VERSION 5.7 ;
BUSBITCHARS "[]" ;
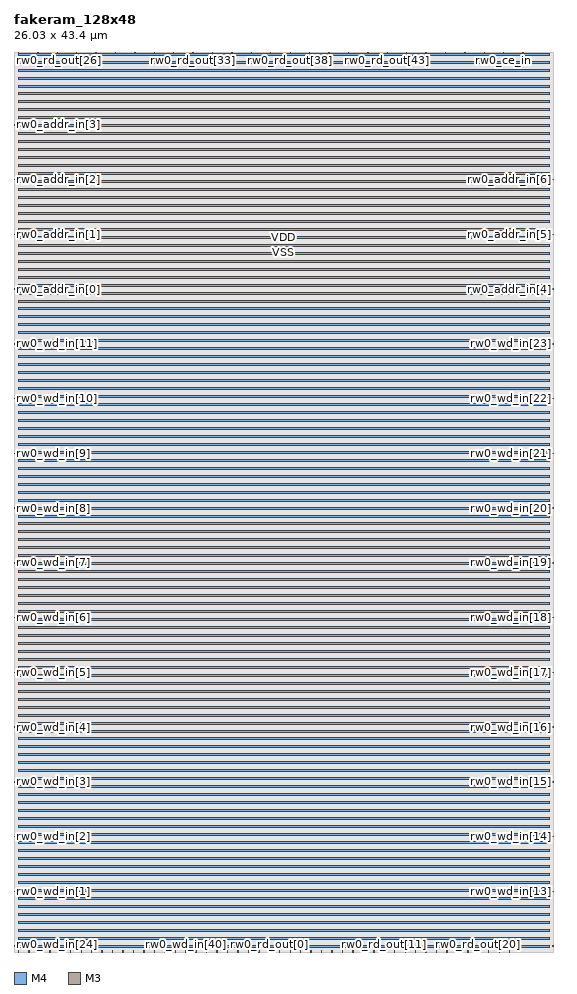
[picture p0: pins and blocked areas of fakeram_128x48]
MACRO fakeram_128x48
  FOREIGN fakeram_128x48 0 0 ;
  SYMMETRY X Y R90 ;
  SIZE 26.030 BY 43.400 ;
  CLASS BLOCK ;
  PIN rw0_wd_in[0]
    DIRECTION INPUT ;
    USE SIGNAL ;
    SHAPE ABUTMENT ;
    PORT
      LAYER M4 ;
      RECT 0.000 0.276 0.072 0.300 ;
    END
  END rw0_wd_in[0]
  PIN rw0_wd_in[1]
    DIRECTION INPUT ;
    USE SIGNAL ;
    SHAPE ABUTMENT ;
    PORT
      LAYER M4 ;
      RECT 0.000 2.916 0.072 2.940 ;
    END
  END rw0_wd_in[1]
  PIN rw0_wd_in[2]
    DIRECTION INPUT ;
    USE SIGNAL ;
    SHAPE ABUTMENT ;
    PORT
      LAYER M4 ;
      RECT 0.000 5.556 0.072 5.580 ;
    END
  END rw0_wd_in[2]
  PIN rw0_wd_in[3]
    DIRECTION INPUT ;
    USE SIGNAL ;
    SHAPE ABUTMENT ;
    PORT
      LAYER M4 ;
      RECT 0.000 8.196 0.072 8.220 ;
    END
  END rw0_wd_in[3]
  PIN rw0_wd_in[4]
    DIRECTION INPUT ;
    USE SIGNAL ;
    SHAPE ABUTMENT ;
    PORT
      LAYER M4 ;
      RECT 0.000 10.836 0.072 10.860 ;
    END
  END rw0_wd_in[4]
  PIN rw0_wd_in[5]
    DIRECTION INPUT ;
    USE SIGNAL ;
    SHAPE ABUTMENT ;
    PORT
      LAYER M4 ;
      RECT 0.000 13.476 0.072 13.500 ;
    END
  END rw0_wd_in[5]
  PIN rw0_wd_in[6]
    DIRECTION INPUT ;
    USE SIGNAL ;
    SHAPE ABUTMENT ;
    PORT
      LAYER M4 ;
      RECT 0.000 16.116 0.072 16.140 ;
    END
  END rw0_wd_in[6]
  PIN rw0_wd_in[7]
    DIRECTION INPUT ;
    USE SIGNAL ;
    SHAPE ABUTMENT ;
    PORT
      LAYER M4 ;
      RECT 0.000 18.756 0.072 18.780 ;
    END
  END rw0_wd_in[7]
  PIN rw0_wd_in[8]
    DIRECTION INPUT ;
    USE SIGNAL ;
    SHAPE ABUTMENT ;
    PORT
      LAYER M4 ;
      RECT 0.000 21.396 0.072 21.420 ;
    END
  END rw0_wd_in[8]
  PIN rw0_wd_in[9]
    DIRECTION INPUT ;
    USE SIGNAL ;
    SHAPE ABUTMENT ;
    PORT
      LAYER M4 ;
      RECT 0.000 24.036 0.072 24.060 ;
    END
  END rw0_wd_in[9]
  PIN rw0_wd_in[10]
    DIRECTION INPUT ;
    USE SIGNAL ;
    SHAPE ABUTMENT ;
    PORT
      LAYER M4 ;
      RECT 0.000 26.676 0.072 26.700 ;
    END
  END rw0_wd_in[10]
  PIN rw0_wd_in[11]
    DIRECTION INPUT ;
    USE SIGNAL ;
    SHAPE ABUTMENT ;
    PORT
      LAYER M4 ;
      RECT 0.000 29.316 0.072 29.340 ;
    END
  END rw0_wd_in[11]
  PIN rw0_wd_in[12]
    DIRECTION INPUT ;
    USE SIGNAL ;
    SHAPE ABUTMENT ;
    PORT
      LAYER M4 ;
      RECT 25.958 0.276 26.030 0.300 ;
    END
  END rw0_wd_in[12]
  PIN rw0_wd_in[13]
    DIRECTION INPUT ;
    USE SIGNAL ;
    SHAPE ABUTMENT ;
    PORT
      LAYER M4 ;
      RECT 25.958 2.916 26.030 2.940 ;
    END
  END rw0_wd_in[13]
  PIN rw0_wd_in[14]
    DIRECTION INPUT ;
    USE SIGNAL ;
    SHAPE ABUTMENT ;
    PORT
      LAYER M4 ;
      RECT 25.958 5.556 26.030 5.580 ;
    END
  END rw0_wd_in[14]
  PIN rw0_wd_in[15]
    DIRECTION INPUT ;
    USE SIGNAL ;
    SHAPE ABUTMENT ;
    PORT
      LAYER M4 ;
      RECT 25.958 8.196 26.030 8.220 ;
    END
  END rw0_wd_in[15]
  PIN rw0_wd_in[16]
    DIRECTION INPUT ;
    USE SIGNAL ;
    SHAPE ABUTMENT ;
    PORT
      LAYER M4 ;
      RECT 25.958 10.836 26.030 10.860 ;
    END
  END rw0_wd_in[16]
  PIN rw0_wd_in[17]
    DIRECTION INPUT ;
    USE SIGNAL ;
    SHAPE ABUTMENT ;
    PORT
      LAYER M4 ;
      RECT 25.958 13.476 26.030 13.500 ;
    END
  END rw0_wd_in[17]
  PIN rw0_wd_in[18]
    DIRECTION INPUT ;
    USE SIGNAL ;
    SHAPE ABUTMENT ;
    PORT
      LAYER M4 ;
      RECT 25.958 16.116 26.030 16.140 ;
    END
  END rw0_wd_in[18]
  PIN rw0_wd_in[19]
    DIRECTION INPUT ;
    USE SIGNAL ;
    SHAPE ABUTMENT ;
    PORT
      LAYER M4 ;
      RECT 25.958 18.756 26.030 18.780 ;
    END
  END rw0_wd_in[19]
  PIN rw0_wd_in[20]
    DIRECTION INPUT ;
    USE SIGNAL ;
    SHAPE ABUTMENT ;
    PORT
      LAYER M4 ;
      RECT 25.958 21.396 26.030 21.420 ;
    END
  END rw0_wd_in[20]
  PIN rw0_wd_in[21]
    DIRECTION INPUT ;
    USE SIGNAL ;
    SHAPE ABUTMENT ;
    PORT
      LAYER M4 ;
      RECT 25.958 24.036 26.030 24.060 ;
    END
  END rw0_wd_in[21]
  PIN rw0_wd_in[22]
    DIRECTION INPUT ;
    USE SIGNAL ;
    SHAPE ABUTMENT ;
    PORT
      LAYER M4 ;
      RECT 25.958 26.676 26.030 26.700 ;
    END
  END rw0_wd_in[22]
  PIN rw0_wd_in[23]
    DIRECTION INPUT ;
    USE SIGNAL ;
    SHAPE ABUTMENT ;
    PORT
      LAYER M4 ;
      RECT 25.958 29.316 26.030 29.340 ;
    END
  END rw0_wd_in[23]
  PIN rw0_wd_in[24]
    DIRECTION INPUT ;
    USE SIGNAL ;
    SHAPE ABUTMENT ;
    PORT
      LAYER M3 ;
      RECT 0.207 0.000 0.225 0.054 ;
    END
  END rw0_wd_in[24]
  PIN rw0_wd_in[25]
    DIRECTION INPUT ;
    USE SIGNAL ;
    SHAPE ABUTMENT ;
    PORT
      LAYER M3 ;
      RECT 0.711 0.000 0.729 0.054 ;
    END
  END rw0_wd_in[25]
  PIN rw0_wd_in[26]
    DIRECTION INPUT ;
    USE SIGNAL ;
    SHAPE ABUTMENT ;
    PORT
      LAYER M3 ;
      RECT 1.215 0.000 1.233 0.054 ;
    END
  END rw0_wd_in[26]
  PIN rw0_wd_in[27]
    DIRECTION INPUT ;
    USE SIGNAL ;
    SHAPE ABUTMENT ;
    PORT
      LAYER M3 ;
      RECT 1.719 0.000 1.737 0.054 ;
    END
  END rw0_wd_in[27]
  PIN rw0_wd_in[28]
    DIRECTION INPUT ;
    USE SIGNAL ;
    SHAPE ABUTMENT ;
    PORT
      LAYER M3 ;
      RECT 2.223 0.000 2.241 0.054 ;
    END
  END rw0_wd_in[28]
  PIN rw0_wd_in[29]
    DIRECTION INPUT ;
    USE SIGNAL ;
    SHAPE ABUTMENT ;
    PORT
      LAYER M3 ;
      RECT 2.727 0.000 2.745 0.054 ;
    END
  END rw0_wd_in[29]
  PIN rw0_wd_in[30]
    DIRECTION INPUT ;
    USE SIGNAL ;
    SHAPE ABUTMENT ;
    PORT
      LAYER M3 ;
      RECT 3.231 0.000 3.249 0.054 ;
    END
  END rw0_wd_in[30]
  PIN rw0_wd_in[31]
    DIRECTION INPUT ;
    USE SIGNAL ;
    SHAPE ABUTMENT ;
    PORT
      LAYER M3 ;
      RECT 3.735 0.000 3.753 0.054 ;
    END
  END rw0_wd_in[31]
  PIN rw0_wd_in[32]
    DIRECTION INPUT ;
    USE SIGNAL ;
    SHAPE ABUTMENT ;
    PORT
      LAYER M3 ;
      RECT 4.239 0.000 4.257 0.054 ;
    END
  END rw0_wd_in[32]
  PIN rw0_wd_in[33]
    DIRECTION INPUT ;
    USE SIGNAL ;
    SHAPE ABUTMENT ;
    PORT
      LAYER M3 ;
      RECT 4.743 0.000 4.761 0.054 ;
    END
  END rw0_wd_in[33]
  PIN rw0_wd_in[34]
    DIRECTION INPUT ;
    USE SIGNAL ;
    SHAPE ABUTMENT ;
    PORT
      LAYER M3 ;
      RECT 5.247 0.000 5.265 0.054 ;
    END
  END rw0_wd_in[34]
  PIN rw0_wd_in[35]
    DIRECTION INPUT ;
    USE SIGNAL ;
    SHAPE ABUTMENT ;
    PORT
      LAYER M3 ;
      RECT 5.751 0.000 5.769 0.054 ;
    END
  END rw0_wd_in[35]
  PIN rw0_wd_in[36]
    DIRECTION INPUT ;
    USE SIGNAL ;
    SHAPE ABUTMENT ;
    PORT
      LAYER M3 ;
      RECT 6.255 0.000 6.273 0.054 ;
    END
  END rw0_wd_in[36]
  PIN rw0_wd_in[37]
    DIRECTION INPUT ;
    USE SIGNAL ;
    SHAPE ABUTMENT ;
    PORT
      LAYER M3 ;
      RECT 6.759 0.000 6.777 0.054 ;
    END
  END rw0_wd_in[37]
  PIN rw0_wd_in[38]
    DIRECTION INPUT ;
    USE SIGNAL ;
    SHAPE ABUTMENT ;
    PORT
      LAYER M3 ;
      RECT 7.263 0.000 7.281 0.054 ;
    END
  END rw0_wd_in[38]
  PIN rw0_wd_in[39]
    DIRECTION INPUT ;
    USE SIGNAL ;
    SHAPE ABUTMENT ;
    PORT
      LAYER M3 ;
      RECT 7.767 0.000 7.785 0.054 ;
    END
  END rw0_wd_in[39]
  PIN rw0_wd_in[40]
    DIRECTION INPUT ;
    USE SIGNAL ;
    SHAPE ABUTMENT ;
    PORT
      LAYER M3 ;
      RECT 8.271 0.000 8.289 0.054 ;
    END
  END rw0_wd_in[40]
  PIN rw0_wd_in[41]
    DIRECTION INPUT ;
    USE SIGNAL ;
    SHAPE ABUTMENT ;
    PORT
      LAYER M3 ;
      RECT 8.775 0.000 8.793 0.054 ;
    END
  END rw0_wd_in[41]
  PIN rw0_wd_in[42]
    DIRECTION INPUT ;
    USE SIGNAL ;
    SHAPE ABUTMENT ;
    PORT
      LAYER M3 ;
      RECT 9.279 0.000 9.297 0.054 ;
    END
  END rw0_wd_in[42]
  PIN rw0_wd_in[43]
    DIRECTION INPUT ;
    USE SIGNAL ;
    SHAPE ABUTMENT ;
    PORT
      LAYER M3 ;
      RECT 9.783 0.000 9.801 0.054 ;
    END
  END rw0_wd_in[43]
  PIN rw0_wd_in[44]
    DIRECTION INPUT ;
    USE SIGNAL ;
    SHAPE ABUTMENT ;
    PORT
      LAYER M3 ;
      RECT 10.287 0.000 10.305 0.054 ;
    END
  END rw0_wd_in[44]
  PIN rw0_wd_in[45]
    DIRECTION INPUT ;
    USE SIGNAL ;
    SHAPE ABUTMENT ;
    PORT
      LAYER M3 ;
      RECT 10.791 0.000 10.809 0.054 ;
    END
  END rw0_wd_in[45]
  PIN rw0_wd_in[46]
    DIRECTION INPUT ;
    USE SIGNAL ;
    SHAPE ABUTMENT ;
    PORT
      LAYER M3 ;
      RECT 11.295 0.000 11.313 0.054 ;
    END
  END rw0_wd_in[46]
  PIN rw0_wd_in[47]
    DIRECTION INPUT ;
    USE SIGNAL ;
    SHAPE ABUTMENT ;
    PORT
      LAYER M3 ;
      RECT 11.799 0.000 11.817 0.054 ;
    END
  END rw0_wd_in[47]
  PIN rw0_rd_out[0]
    DIRECTION OUTPUT ;
    USE SIGNAL ;
    SHAPE ABUTMENT ;
    PORT
      LAYER M3 ;
      RECT 12.303 0.000 12.321 0.054 ;
    END
  END rw0_rd_out[0]
  PIN rw0_rd_out[1]
    DIRECTION OUTPUT ;
    USE SIGNAL ;
    SHAPE ABUTMENT ;
    PORT
      LAYER M3 ;
      RECT 12.807 0.000 12.825 0.054 ;
    END
  END rw0_rd_out[1]
  PIN rw0_rd_out[2]
    DIRECTION OUTPUT ;
    USE SIGNAL ;
    SHAPE ABUTMENT ;
    PORT
      LAYER M3 ;
      RECT 13.311 0.000 13.329 0.054 ;
    END
  END rw0_rd_out[2]
  PIN rw0_rd_out[3]
    DIRECTION OUTPUT ;
    USE SIGNAL ;
    SHAPE ABUTMENT ;
    PORT
      LAYER M3 ;
      RECT 13.815 0.000 13.833 0.054 ;
    END
  END rw0_rd_out[3]
  PIN rw0_rd_out[4]
    DIRECTION OUTPUT ;
    USE SIGNAL ;
    SHAPE ABUTMENT ;
    PORT
      LAYER M3 ;
      RECT 14.319 0.000 14.337 0.054 ;
    END
  END rw0_rd_out[4]
  PIN rw0_rd_out[5]
    DIRECTION OUTPUT ;
    USE SIGNAL ;
    SHAPE ABUTMENT ;
    PORT
      LAYER M3 ;
      RECT 14.823 0.000 14.841 0.054 ;
    END
  END rw0_rd_out[5]
  PIN rw0_rd_out[6]
    DIRECTION OUTPUT ;
    USE SIGNAL ;
    SHAPE ABUTMENT ;
    PORT
      LAYER M3 ;
      RECT 15.327 0.000 15.345 0.054 ;
    END
  END rw0_rd_out[6]
  PIN rw0_rd_out[7]
    DIRECTION OUTPUT ;
    USE SIGNAL ;
    SHAPE ABUTMENT ;
    PORT
      LAYER M3 ;
      RECT 15.831 0.000 15.849 0.054 ;
    END
  END rw0_rd_out[7]
  PIN rw0_rd_out[8]
    DIRECTION OUTPUT ;
    USE SIGNAL ;
    SHAPE ABUTMENT ;
    PORT
      LAYER M3 ;
      RECT 16.335 0.000 16.353 0.054 ;
    END
  END rw0_rd_out[8]
  PIN rw0_rd_out[9]
    DIRECTION OUTPUT ;
    USE SIGNAL ;
    SHAPE ABUTMENT ;
    PORT
      LAYER M3 ;
      RECT 16.839 0.000 16.857 0.054 ;
    END
  END rw0_rd_out[9]
  PIN rw0_rd_out[10]
    DIRECTION OUTPUT ;
    USE SIGNAL ;
    SHAPE ABUTMENT ;
    PORT
      LAYER M3 ;
      RECT 17.343 0.000 17.361 0.054 ;
    END
  END rw0_rd_out[10]
  PIN rw0_rd_out[11]
    DIRECTION OUTPUT ;
    USE SIGNAL ;
    SHAPE ABUTMENT ;
    PORT
      LAYER M3 ;
      RECT 17.847 0.000 17.865 0.054 ;
    END
  END rw0_rd_out[11]
  PIN rw0_rd_out[12]
    DIRECTION OUTPUT ;
    USE SIGNAL ;
    SHAPE ABUTMENT ;
    PORT
      LAYER M3 ;
      RECT 18.351 0.000 18.369 0.054 ;
    END
  END rw0_rd_out[12]
  PIN rw0_rd_out[13]
    DIRECTION OUTPUT ;
    USE SIGNAL ;
    SHAPE ABUTMENT ;
    PORT
      LAYER M3 ;
      RECT 18.855 0.000 18.873 0.054 ;
    END
  END rw0_rd_out[13]
  PIN rw0_rd_out[14]
    DIRECTION OUTPUT ;
    USE SIGNAL ;
    SHAPE ABUTMENT ;
    PORT
      LAYER M3 ;
      RECT 19.359 0.000 19.377 0.054 ;
    END
  END rw0_rd_out[14]
  PIN rw0_rd_out[15]
    DIRECTION OUTPUT ;
    USE SIGNAL ;
    SHAPE ABUTMENT ;
    PORT
      LAYER M3 ;
      RECT 19.863 0.000 19.881 0.054 ;
    END
  END rw0_rd_out[15]
  PIN rw0_rd_out[16]
    DIRECTION OUTPUT ;
    USE SIGNAL ;
    SHAPE ABUTMENT ;
    PORT
      LAYER M3 ;
      RECT 20.367 0.000 20.385 0.054 ;
    END
  END rw0_rd_out[16]
  PIN rw0_rd_out[17]
    DIRECTION OUTPUT ;
    USE SIGNAL ;
    SHAPE ABUTMENT ;
    PORT
      LAYER M3 ;
      RECT 20.871 0.000 20.889 0.054 ;
    END
  END rw0_rd_out[17]
  PIN rw0_rd_out[18]
    DIRECTION OUTPUT ;
    USE SIGNAL ;
    SHAPE ABUTMENT ;
    PORT
      LAYER M3 ;
      RECT 21.375 0.000 21.393 0.054 ;
    END
  END rw0_rd_out[18]
  PIN rw0_rd_out[19]
    DIRECTION OUTPUT ;
    USE SIGNAL ;
    SHAPE ABUTMENT ;
    PORT
      LAYER M3 ;
      RECT 21.879 0.000 21.897 0.054 ;
    END
  END rw0_rd_out[19]
  PIN rw0_rd_out[20]
    DIRECTION OUTPUT ;
    USE SIGNAL ;
    SHAPE ABUTMENT ;
    PORT
      LAYER M3 ;
      RECT 22.383 0.000 22.401 0.054 ;
    END
  END rw0_rd_out[20]
  PIN rw0_rd_out[21]
    DIRECTION OUTPUT ;
    USE SIGNAL ;
    SHAPE ABUTMENT ;
    PORT
      LAYER M3 ;
      RECT 22.887 0.000 22.905 0.054 ;
    END
  END rw0_rd_out[21]
  PIN rw0_rd_out[22]
    DIRECTION OUTPUT ;
    USE SIGNAL ;
    SHAPE ABUTMENT ;
    PORT
      LAYER M3 ;
      RECT 23.391 0.000 23.409 0.054 ;
    END
  END rw0_rd_out[22]
  PIN rw0_rd_out[23]
    DIRECTION OUTPUT ;
    USE SIGNAL ;
    SHAPE ABUTMENT ;
    PORT
      LAYER M3 ;
      RECT 23.895 0.000 23.913 0.054 ;
    END
  END rw0_rd_out[23]
  PIN rw0_rd_out[24]
    DIRECTION OUTPUT ;
    USE SIGNAL ;
    SHAPE ABUTMENT ;
    PORT
      LAYER M3 ;
      RECT 0.207 43.346 0.225 43.400 ;
    END
  END rw0_rd_out[24]
  PIN rw0_rd_out[25]
    DIRECTION OUTPUT ;
    USE SIGNAL ;
    SHAPE ABUTMENT ;
    PORT
      LAYER M3 ;
      RECT 1.143 43.346 1.161 43.400 ;
    END
  END rw0_rd_out[25]
  PIN rw0_rd_out[26]
    DIRECTION OUTPUT ;
    USE SIGNAL ;
    SHAPE ABUTMENT ;
    PORT
      LAYER M3 ;
      RECT 2.079 43.346 2.097 43.400 ;
    END
  END rw0_rd_out[26]
  PIN rw0_rd_out[27]
    DIRECTION OUTPUT ;
    USE SIGNAL ;
    SHAPE ABUTMENT ;
    PORT
      LAYER M3 ;
      RECT 3.015 43.346 3.033 43.400 ;
    END
  END rw0_rd_out[27]
  PIN rw0_rd_out[28]
    DIRECTION OUTPUT ;
    USE SIGNAL ;
    SHAPE ABUTMENT ;
    PORT
      LAYER M3 ;
      RECT 3.951 43.346 3.969 43.400 ;
    END
  END rw0_rd_out[28]
  PIN rw0_rd_out[29]
    DIRECTION OUTPUT ;
    USE SIGNAL ;
    SHAPE ABUTMENT ;
    PORT
      LAYER M3 ;
      RECT 4.887 43.346 4.905 43.400 ;
    END
  END rw0_rd_out[29]
  PIN rw0_rd_out[30]
    DIRECTION OUTPUT ;
    USE SIGNAL ;
    SHAPE ABUTMENT ;
    PORT
      LAYER M3 ;
      RECT 5.823 43.346 5.841 43.400 ;
    END
  END rw0_rd_out[30]
  PIN rw0_rd_out[31]
    DIRECTION OUTPUT ;
    USE SIGNAL ;
    SHAPE ABUTMENT ;
    PORT
      LAYER M3 ;
      RECT 6.759 43.346 6.777 43.400 ;
    END
  END rw0_rd_out[31]
  PIN rw0_rd_out[32]
    DIRECTION OUTPUT ;
    USE SIGNAL ;
    SHAPE ABUTMENT ;
    PORT
      LAYER M3 ;
      RECT 7.695 43.346 7.713 43.400 ;
    END
  END rw0_rd_out[32]
  PIN rw0_rd_out[33]
    DIRECTION OUTPUT ;
    USE SIGNAL ;
    SHAPE ABUTMENT ;
    PORT
      LAYER M3 ;
      RECT 8.631 43.346 8.649 43.400 ;
    END
  END rw0_rd_out[33]
  PIN rw0_rd_out[34]
    DIRECTION OUTPUT ;
    USE SIGNAL ;
    SHAPE ABUTMENT ;
    PORT
      LAYER M3 ;
      RECT 9.567 43.346 9.585 43.400 ;
    END
  END rw0_rd_out[34]
  PIN rw0_rd_out[35]
    DIRECTION OUTPUT ;
    USE SIGNAL ;
    SHAPE ABUTMENT ;
    PORT
      LAYER M3 ;
      RECT 10.503 43.346 10.521 43.400 ;
    END
  END rw0_rd_out[35]
  PIN rw0_rd_out[36]
    DIRECTION OUTPUT ;
    USE SIGNAL ;
    SHAPE ABUTMENT ;
    PORT
      LAYER M3 ;
      RECT 11.439 43.346 11.457 43.400 ;
    END
  END rw0_rd_out[36]
  PIN rw0_rd_out[37]
    DIRECTION OUTPUT ;
    USE SIGNAL ;
    SHAPE ABUTMENT ;
    PORT
      LAYER M3 ;
      RECT 12.375 43.346 12.393 43.400 ;
    END
  END rw0_rd_out[37]
  PIN rw0_rd_out[38]
    DIRECTION OUTPUT ;
    USE SIGNAL ;
    SHAPE ABUTMENT ;
    PORT
      LAYER M3 ;
      RECT 13.311 43.346 13.329 43.400 ;
    END
  END rw0_rd_out[38]
  PIN rw0_rd_out[39]
    DIRECTION OUTPUT ;
    USE SIGNAL ;
    SHAPE ABUTMENT ;
    PORT
      LAYER M3 ;
      RECT 14.247 43.346 14.265 43.400 ;
    END
  END rw0_rd_out[39]
  PIN rw0_rd_out[40]
    DIRECTION OUTPUT ;
    USE SIGNAL ;
    SHAPE ABUTMENT ;
    PORT
      LAYER M3 ;
      RECT 15.183 43.346 15.201 43.400 ;
    END
  END rw0_rd_out[40]
  PIN rw0_rd_out[41]
    DIRECTION OUTPUT ;
    USE SIGNAL ;
    SHAPE ABUTMENT ;
    PORT
      LAYER M3 ;
      RECT 16.119 43.346 16.137 43.400 ;
    END
  END rw0_rd_out[41]
  PIN rw0_rd_out[42]
    DIRECTION OUTPUT ;
    USE SIGNAL ;
    SHAPE ABUTMENT ;
    PORT
      LAYER M3 ;
      RECT 17.055 43.346 17.073 43.400 ;
    END
  END rw0_rd_out[42]
  PIN rw0_rd_out[43]
    DIRECTION OUTPUT ;
    USE SIGNAL ;
    SHAPE ABUTMENT ;
    PORT
      LAYER M3 ;
      RECT 17.991 43.346 18.009 43.400 ;
    END
  END rw0_rd_out[43]
  PIN rw0_rd_out[44]
    DIRECTION OUTPUT ;
    USE SIGNAL ;
    SHAPE ABUTMENT ;
    PORT
      LAYER M3 ;
      RECT 18.927 43.346 18.945 43.400 ;
    END
  END rw0_rd_out[44]
  PIN rw0_rd_out[45]
    DIRECTION OUTPUT ;
    USE SIGNAL ;
    SHAPE ABUTMENT ;
    PORT
      LAYER M3 ;
      RECT 19.863 43.346 19.881 43.400 ;
    END
  END rw0_rd_out[45]
  PIN rw0_rd_out[46]
    DIRECTION OUTPUT ;
    USE SIGNAL ;
    SHAPE ABUTMENT ;
    PORT
      LAYER M3 ;
      RECT 20.799 43.346 20.817 43.400 ;
    END
  END rw0_rd_out[46]
  PIN rw0_rd_out[47]
    DIRECTION OUTPUT ;
    USE SIGNAL ;
    SHAPE ABUTMENT ;
    PORT
      LAYER M3 ;
      RECT 21.735 43.346 21.753 43.400 ;
    END
  END rw0_rd_out[47]
  PIN rw0_addr_in[0]
    DIRECTION INPUT ;
    USE SIGNAL ;
    SHAPE ABUTMENT ;
    PORT
      LAYER M4 ;
      RECT 0.000 31.956 0.072 31.980 ;
    END
  END rw0_addr_in[0]
  PIN rw0_addr_in[1]
    DIRECTION INPUT ;
    USE SIGNAL ;
    SHAPE ABUTMENT ;
    PORT
      LAYER M4 ;
      RECT 0.000 34.596 0.072 34.620 ;
    END
  END rw0_addr_in[1]
  PIN rw0_addr_in[2]
    DIRECTION INPUT ;
    USE SIGNAL ;
    SHAPE ABUTMENT ;
    PORT
      LAYER M4 ;
      RECT 0.000 37.236 0.072 37.260 ;
    END
  END rw0_addr_in[2]
  PIN rw0_addr_in[3]
    DIRECTION INPUT ;
    USE SIGNAL ;
    SHAPE ABUTMENT ;
    PORT
      LAYER M4 ;
      RECT 0.000 39.876 0.072 39.900 ;
    END
  END rw0_addr_in[3]
  PIN rw0_addr_in[4]
    DIRECTION INPUT ;
    USE SIGNAL ;
    SHAPE ABUTMENT ;
    PORT
      LAYER M4 ;
      RECT 25.958 31.956 26.030 31.980 ;
    END
  END rw0_addr_in[4]
  PIN rw0_addr_in[5]
    DIRECTION INPUT ;
    USE SIGNAL ;
    SHAPE ABUTMENT ;
    PORT
      LAYER M4 ;
      RECT 25.958 34.596 26.030 34.620 ;
    END
  END rw0_addr_in[5]
  PIN rw0_addr_in[6]
    DIRECTION INPUT ;
    USE SIGNAL ;
    SHAPE ABUTMENT ;
    PORT
      LAYER M4 ;
      RECT 25.958 37.236 26.030 37.260 ;
    END
  END rw0_addr_in[6]
  PIN rw0_we_in
    DIRECTION INPUT ;
    USE SIGNAL ;
    SHAPE ABUTMENT ;
    PORT
      LAYER M3 ;
      RECT 22.671 43.346 22.689 43.400 ;
    END
  END rw0_we_in
  PIN rw0_ce_in
    DIRECTION INPUT ;
    USE SIGNAL ;
    SHAPE ABUTMENT ;
    PORT
      LAYER M3 ;
      RECT 23.607 43.346 23.625 43.400 ;
    END
  END rw0_ce_in
  PIN rw0_clk
    DIRECTION INPUT ;
    USE SIGNAL ;
    SHAPE ABUTMENT ;
    PORT
      LAYER M3 ;
      RECT 24.543 43.346 24.561 43.400 ;
    END
  END rw0_clk
  PIN VSS
    DIRECTION INOUT ;
    USE GROUND ;
    PORT
      LAYER M4 ;
      RECT 0.216 0.240 25.814 0.336 ;
      RECT 0.216 1.008 25.814 1.104 ;
      RECT 0.216 1.776 25.814 1.872 ;
      RECT 0.216 2.544 25.814 2.640 ;
      RECT 0.216 3.312 25.814 3.408 ;
      RECT 0.216 4.080 25.814 4.176 ;
      RECT 0.216 4.848 25.814 4.944 ;
      RECT 0.216 5.616 25.814 5.712 ;
      RECT 0.216 6.384 25.814 6.480 ;
      RECT 0.216 7.152 25.814 7.248 ;
      RECT 0.216 7.920 25.814 8.016 ;
      RECT 0.216 8.688 25.814 8.784 ;
      RECT 0.216 9.456 25.814 9.552 ;
      RECT 0.216 10.224 25.814 10.320 ;
      RECT 0.216 10.992 25.814 11.088 ;
      RECT 0.216 11.760 25.814 11.856 ;
      RECT 0.216 12.528 25.814 12.624 ;
      RECT 0.216 13.296 25.814 13.392 ;
      RECT 0.216 14.064 25.814 14.160 ;
      RECT 0.216 14.832 25.814 14.928 ;
      RECT 0.216 15.600 25.814 15.696 ;
      RECT 0.216 16.368 25.814 16.464 ;
      RECT 0.216 17.136 25.814 17.232 ;
      RECT 0.216 17.904 25.814 18.000 ;
      RECT 0.216 18.672 25.814 18.768 ;
      RECT 0.216 19.440 25.814 19.536 ;
      RECT 0.216 20.208 25.814 20.304 ;
      RECT 0.216 20.976 25.814 21.072 ;
      RECT 0.216 21.744 25.814 21.840 ;
      RECT 0.216 22.512 25.814 22.608 ;
      RECT 0.216 23.280 25.814 23.376 ;
      RECT 0.216 24.048 25.814 24.144 ;
      RECT 0.216 24.816 25.814 24.912 ;
      RECT 0.216 25.584 25.814 25.680 ;
      RECT 0.216 26.352 25.814 26.448 ;
      RECT 0.216 27.120 25.814 27.216 ;
      RECT 0.216 27.888 25.814 27.984 ;
      RECT 0.216 28.656 25.814 28.752 ;
      RECT 0.216 29.424 25.814 29.520 ;
      RECT 0.216 30.192 25.814 30.288 ;
      RECT 0.216 30.960 25.814 31.056 ;
      RECT 0.216 31.728 25.814 31.824 ;
      RECT 0.216 32.496 25.814 32.592 ;
      RECT 0.216 33.264 25.814 33.360 ;
      RECT 0.216 34.032 25.814 34.128 ;
      RECT 0.216 34.800 25.814 34.896 ;
      RECT 0.216 35.568 25.814 35.664 ;
      RECT 0.216 36.336 25.814 36.432 ;
      RECT 0.216 37.104 25.814 37.200 ;
      RECT 0.216 37.872 25.814 37.968 ;
      RECT 0.216 38.640 25.814 38.736 ;
      RECT 0.216 39.408 25.814 39.504 ;
      RECT 0.216 40.176 25.814 40.272 ;
      RECT 0.216 40.944 25.814 41.040 ;
      RECT 0.216 41.712 25.814 41.808 ;
      RECT 0.216 42.480 25.814 42.576 ;
      RECT 0.216 43.248 25.814 43.344 ;
    END
  END VSS
  PIN VDD
    DIRECTION INOUT ;
    USE POWER ;
    PORT
      LAYER M4 ;
      RECT 0.216 0.624 25.814 0.720 ;
      RECT 0.216 1.392 25.814 1.488 ;
      RECT 0.216 2.160 25.814 2.256 ;
      RECT 0.216 2.928 25.814 3.024 ;
      RECT 0.216 3.696 25.814 3.792 ;
      RECT 0.216 4.464 25.814 4.560 ;
      RECT 0.216 5.232 25.814 5.328 ;
      RECT 0.216 6.000 25.814 6.096 ;
      RECT 0.216 6.768 25.814 6.864 ;
      RECT 0.216 7.536 25.814 7.632 ;
      RECT 0.216 8.304 25.814 8.400 ;
      RECT 0.216 9.072 25.814 9.168 ;
      RECT 0.216 9.840 25.814 9.936 ;
      RECT 0.216 10.608 25.814 10.704 ;
      RECT 0.216 11.376 25.814 11.472 ;
      RECT 0.216 12.144 25.814 12.240 ;
      RECT 0.216 12.912 25.814 13.008 ;
      RECT 0.216 13.680 25.814 13.776 ;
      RECT 0.216 14.448 25.814 14.544 ;
      RECT 0.216 15.216 25.814 15.312 ;
      RECT 0.216 15.984 25.814 16.080 ;
      RECT 0.216 16.752 25.814 16.848 ;
      RECT 0.216 17.520 25.814 17.616 ;
      RECT 0.216 18.288 25.814 18.384 ;
      RECT 0.216 19.056 25.814 19.152 ;
      RECT 0.216 19.824 25.814 19.920 ;
      RECT 0.216 20.592 25.814 20.688 ;
      RECT 0.216 21.360 25.814 21.456 ;
      RECT 0.216 22.128 25.814 22.224 ;
      RECT 0.216 22.896 25.814 22.992 ;
      RECT 0.216 23.664 25.814 23.760 ;
      RECT 0.216 24.432 25.814 24.528 ;
      RECT 0.216 25.200 25.814 25.296 ;
      RECT 0.216 25.968 25.814 26.064 ;
      RECT 0.216 26.736 25.814 26.832 ;
      RECT 0.216 27.504 25.814 27.600 ;
      RECT 0.216 28.272 25.814 28.368 ;
      RECT 0.216 29.040 25.814 29.136 ;
      RECT 0.216 29.808 25.814 29.904 ;
      RECT 0.216 30.576 25.814 30.672 ;
      RECT 0.216 31.344 25.814 31.440 ;
      RECT 0.216 32.112 25.814 32.208 ;
      RECT 0.216 32.880 25.814 32.976 ;
      RECT 0.216 33.648 25.814 33.744 ;
      RECT 0.216 34.416 25.814 34.512 ;
      RECT 0.216 35.184 25.814 35.280 ;
      RECT 0.216 35.952 25.814 36.048 ;
      RECT 0.216 36.720 25.814 36.816 ;
      RECT 0.216 37.488 25.814 37.584 ;
      RECT 0.216 38.256 25.814 38.352 ;
      RECT 0.216 39.024 25.814 39.120 ;
      RECT 0.216 39.792 25.814 39.888 ;
      RECT 0.216 40.560 25.814 40.656 ;
      RECT 0.216 41.328 25.814 41.424 ;
      RECT 0.216 42.096 25.814 42.192 ;
      RECT 0.216 42.864 25.814 42.960 ;
    END
  END VDD
  OBS
    LAYER M1 ;
    RECT 0 0 26.030 43.400 ;
    LAYER M2 ;
    RECT 0 0 26.030 43.400 ;
    LAYER M3 ;
    RECT 0 0 26.030 43.400 ;
    LAYER M4 ;
    RECT 0 0 26.030 43.400 ;
  END
END fakeram_128x48

END LIBRARY
